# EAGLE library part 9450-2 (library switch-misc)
MARQUARDT SWITCH

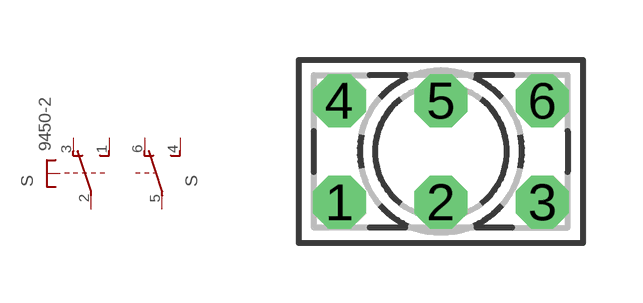
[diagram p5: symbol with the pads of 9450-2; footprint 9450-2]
Designator prefix S; gates 1=TSU- 2=U-2

## 9450-2  [9450-2]
1  1:S  pas
2  1:P  pas
3  1:O  pas
4  2:S  pas
5  2:P  pas
6  2:O  pas

## Footprint 9450-2 (pad centres in mm)
MARQUARDT SWITCH
drill 0.813 octagon: 1 -2.54,-1.27; 2 0,-1.27; 3 2.54,-1.27; 4 -2.54,1.27; 5 0,1.27; 6 2.54,1.27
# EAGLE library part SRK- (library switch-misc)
SWITCH

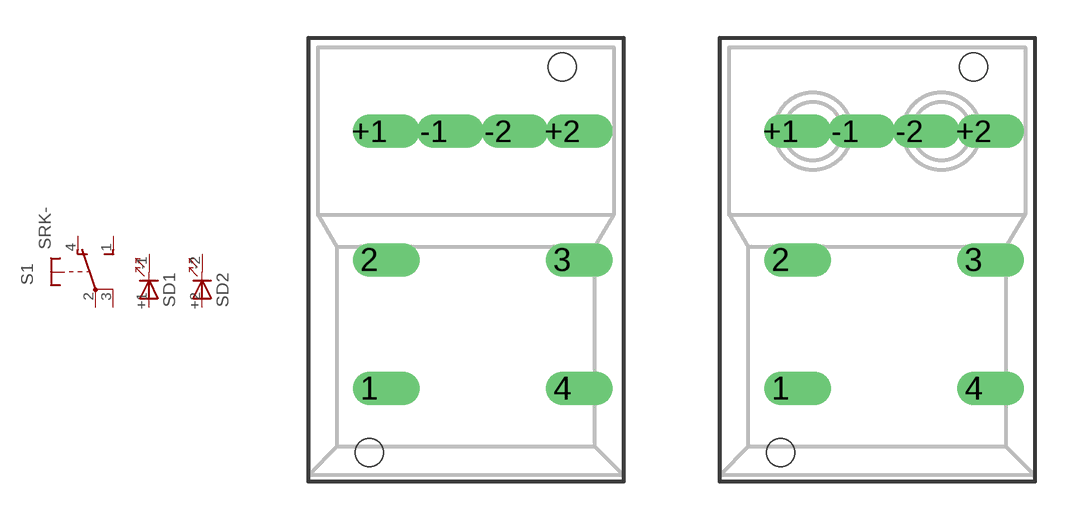
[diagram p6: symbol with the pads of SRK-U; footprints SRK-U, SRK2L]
Designator prefix S; gates D1=KEY-LED D2=KEY-LED 1=TSU1

## SRK-U  [SRK-U]
1  1:S  pas
2  1:P  pas
3  1:P  pas
4  1:O  pas
+1  D1:A  pas
+2  D2:A  pas
-1  D1:C  pas
-2  D2:C  pas

## SRK-2L  [SRK2L]
Pads as for SRK-U

## Footprint SRK-U (pad centres in mm)
SWITCH
drill 0.813 offset: 1 -3.81,-5.08; 2 -3.81,0; 3 3.81,0; 4 3.81,-5.08; +1 -3.81,5.08; +2 3.81,5.08; -1 -1.27,5.08; -2 1.27,5.08
hole 1.118 at 3.81,7.62
hole 1.118 at -3.81,-7.62

## Footprint SRK2L (pad centres in mm)
SWITCH
drill 0.813 offset: 1 -3.81,-5.08; 2 -3.81,0; 3 3.81,0; 4 3.81,-5.08; +1 -3.81,5.08; +2 3.81,5.08; -1 -1.27,5.08; -2 1.27,5.08
hole 1.118 at 3.81,7.62
hole 1.118 at -3.81,-7.62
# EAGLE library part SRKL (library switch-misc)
SWITCH

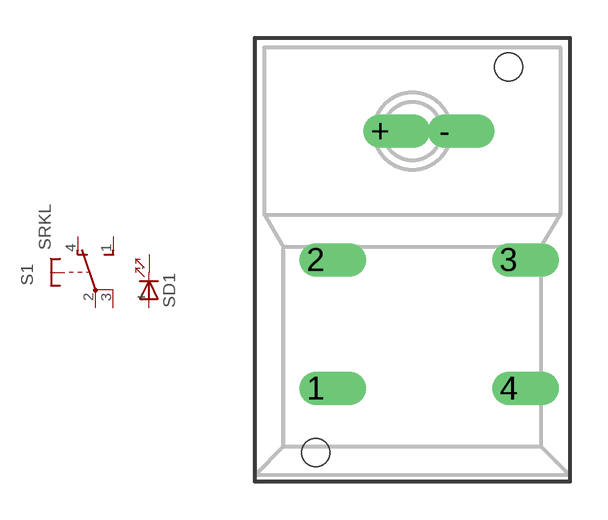
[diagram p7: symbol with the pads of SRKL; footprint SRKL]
Designator prefix S; gates D1=KEY-LED 1=TSU1

## SRKL  [SRKL]
1  1:S  pas
2  1:P  pas
3  1:P  pas
4  1:O  pas
+  D1:A  pas
-  D1:C  pas

## Footprint SRKL (pad centres in mm)
SWITCH
drill 0.813 offset: 1 -3.81,-5.08; 2 -3.81,0; 3 3.81,0; 4 3.81,-5.08; + -1.27,5.08; - 1.27,5.08
hole 1.118 at 3.81,7.62
hole 1.118 at -3.81,-7.62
